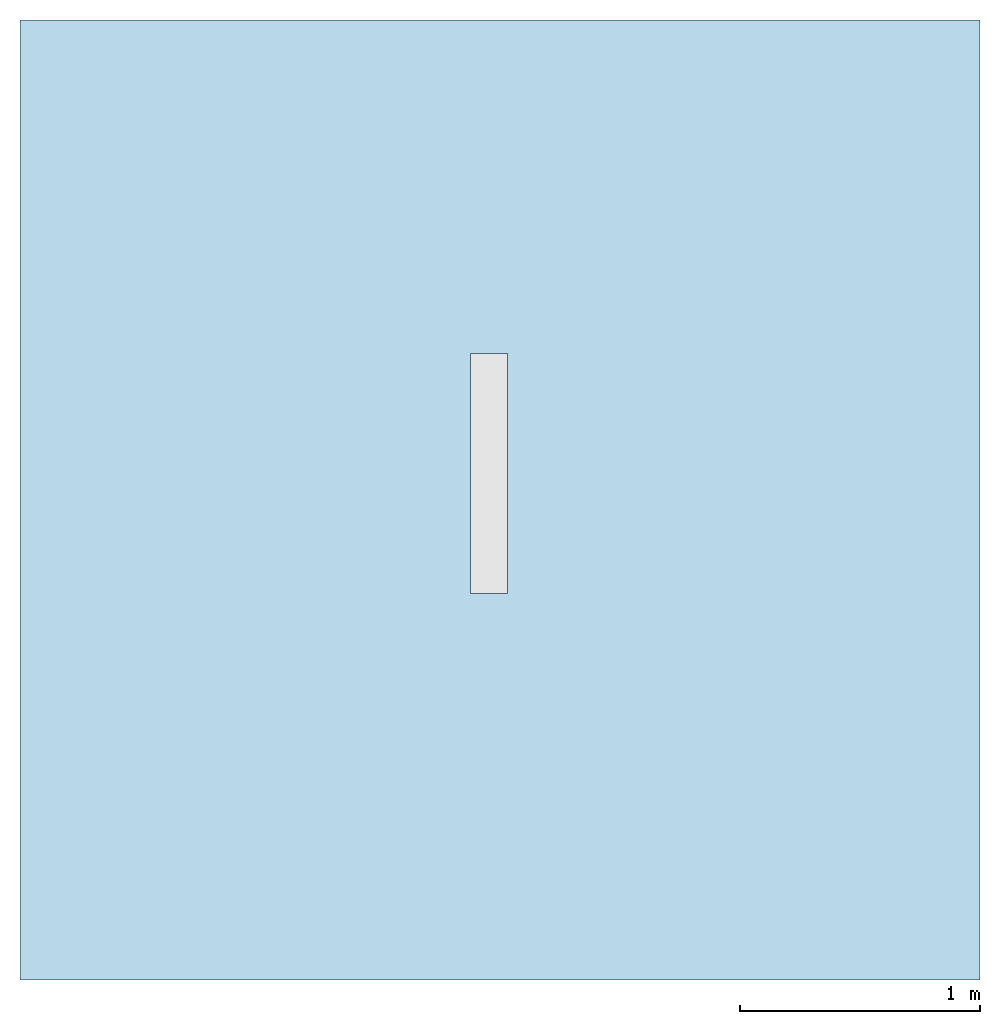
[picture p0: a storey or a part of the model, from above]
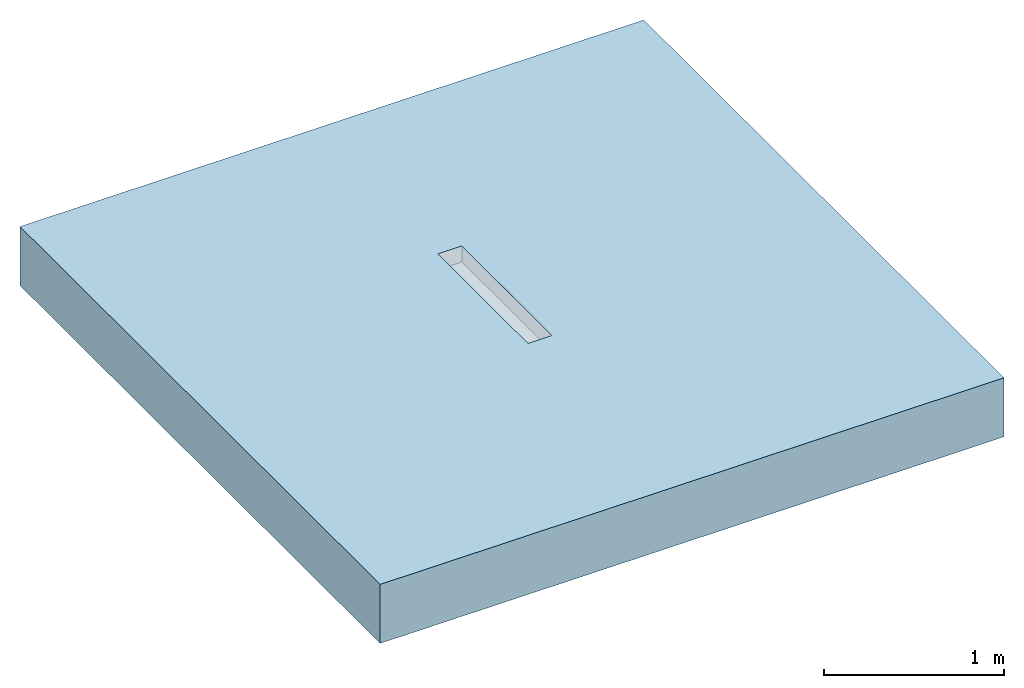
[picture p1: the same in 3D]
Properties of the parts of a building model (IFC2X3)

# File
Description: ViewDefinition [CoordinationView]
File name: 105130 - Straight Channel - 1000mm LG - Invert Depth 95mm.ifc
Time: 2014-03-20T08:44:47
Written by: Autodesk Revit 2013
Made in: 20120221_2030(x64)

# IfcProject, Project Number
LongName: Project Name; Phase: Project Status

# IfcSite, Default
RefLatitude: 42, 21, 30, 344238; RefLongitude: -71, -3, -35, -194702; RefElevation: 0 mm

# IfcBuilding
Pset_BuildingCommon - NumberOfStoreys: 1
Other - Project Address: ## Street City, State Zip; Project Status: Project Status; Client Name: Owner; Project Issue Date: Issue Date; Project Number: Project Number; Project Name: Project Name

# IfcBuildingStorey, Level 1
LongName: Level 1; Elevation: 0 mm
Graphics - Symbol at End 2 Default: yes; Line Pattern: Center; Line Weight: 1; Symbol at End 1 Default: no; Symbol: M_Level Head - Circle: M_Level Head - Circle; Color: 0
Constraints - Elevation Base: 0; Elevation: 0 mm
Dimensions - Computation Height: 0 mm
Identity Data - Structural: no; Name: Level 1; Building Story: yes

# IfcFlowTerminal: 105130 - Straight Channel - 1000mm LG - Invert Depth 95mm, ACO BD Modular 125 Level Invert Straight Channels:105130 - Straight Channel - 1000mm LG - Invert Depth 95mm:105130 - Straight Channel - 1000mm LG - Invert Depth 95mm:202382
In: Level 1
Material: Stainless Steel AISI 304, Polystyrene, High Impact (F)
Dimensions - Grating Length: 1000 mm; Grating End: -1000 mm; Invert Depth Height: 50 mm; Floor Void Height: 107.8 mm; Custom Length: 500 mm; Length: 500 mm; Custom Channel End: -497 mm; Invert Depth: 95 mm; End Connection Plate: 997 mm; Channel End: -997 mm; Height: 95 mm; Standard Length: 1000 mm; Channel Start: -3 mm
Other - PVC Infill (26270): 1000 mm; Rigid PVC Extrusion (49061): 0 mm; Neoprene Gasket: 1; Number: 20; Detail Void Height: 106.3 mm; Flexible PVC Seal (49062): 0 mm; 1000mm Long Channel: yes; Non Standard Length Channel: no; 2000mm Long Channel: no; 500mm Long Channel: no; 3000mm Long Channel: no; Standard Length Channel: yes
Construction - 105530 - Quadrato - Stainless Steel 304 - 500mm long: no; 26270_PVC Infill: yes; 21740 - Ladder - Stainless Steel 304 - 500mm long: no; 105539 - Intercept - Stainless Steel 304 - 500mm long: no; 21741 - Ladder - Stainless Steel 304 - 1000mm long: no; 105844 - Slip Resistant Quadrato Locked - Stainless Steel 304 - 500mm long: no; 10735 - Composite - White Composite - 500mm long: no; 21810 - Grating - Slip Resistant Mesh - Stainless Steel 304 - 1000mm long: no; 105529 - Quadrato - Stainless Steel 304 - 1000mm long: no; 21610 - Grating - Slip Resistant Mesh - Stainless Steel 304 - 1000mm long: no; 21710 - Grating - Slip Resistant Mesh - Stainless Steel 304 - 500mm long: no; End Plate Invert 1: no; 21620 - Grating - Plain Mesh - Stainless Steel 304 - 1000mm long: no; 105842 - Slip Resistant Quadrato - Stainless Steel 304 - 500mm long: no; 96818 - Grating - Heal Safe - Stainless Steel 304 - 1000mm long: no; 105536 - Intercept Locked - Stainless Steel 304 - 1000mm long: no; 105841 - Slip Resistant Quadrato - Stainless Steel 304 - 1000mm long: no; 21720 - Grating - Plain Mesh - Stainless Steel 304 - 500mm long: no; 105847 - Slip Resistant Intercept Locked - Stainless Steel 304 - 1000mm long: no; 105520 - Slotted Locked - Stainless Steel 304 - 1000mm long: no; 105505 - Perforated Locked - Stainless Steel 304 - 500mm long: no; 105846 - Slip Resistant Intercept - Stainless Steel 304 - 500mm long: no; 105843 - Slip Resistant Quadrato Locked - Stainless Steel 304 - 1000mm long: no; 105848 - Slip Resistant Intercept Locked - Stainless Steel 304 - 500mm long: no; 105527 - Quadrato Locked - Stainless Steel 304 - 1000mm long: no; 105519 - Slotted Locked - Stainless Steel 304 - 500mm long: no; 21790 - Plastic - White Plastic - 500mm long: no; 21820 - Grating - Plain Mesh - Stainless Steel 304 - 1000mm long: no; 105537 - Intercept Locked - Stainless Steel 304 - 500mm long: no; 105521 - Slotted Locked - Stainless Steel 304 - 500mm long: no; 105504 - Perforated Locked - Stainless Steel 304 - 1000mm long: no; 402072 - Grating - Heal Safe Locked - Stainless Steel 304 - 500mm long: no; 105845 - Slip Resistant Intercept - Stainless Steel 304 - 1000mm long: no; 105518 - Slotted Locked - Stainless Steel 304 - 1000mm long: no; 49061 & 49062_Vinyl Seal: no; 105528 - Quadrato Locked - Stainless Steel 304 - 500mm long: no; 21910 - Grating - Slip Resistant Mesh - Stainless Steel 304 - 500mm long: no; 105538 - Intercept - Stainless Steel 304 - 1000mm long: no; 402071 - Grating - Heal Safe Locked - Stainless Steel 304 - 1000mm long: no; 15704 - Composite - Black Composite - 500mm long: no; 21690 - Plastic - White Plastic - 1000mm long: no; 96819 - Grating - Heal Safe - Stainless Steel 304 - 500mm long: no; End Plate Invert 2: no; 21920 - Grating - Plain Mesh - Stainless Steel 304 - 500mm long: no; Detail 95mm: yes; Detail 50mm: no; Detail Non Standard Length: no; Detail 125mm: no; Detail 65mm: no; Detail 110mm: no; Detail 80mm: no
Phasing - Phase Created: New Construction
Constraints - Moves With Nearby Elements: no; Level: Level: Level 1
Identity Data - Mark: 1; Manufacturer: ACO Building Drainage; Website: www.acobd.com; E-mail Technical: abdtechnical@aco.co.uk; E-mail Sales: abdcommercial@aco.co.uk; Watermark1: This file is the property of ACO Technologies PLC; Watermarked By: www.acobd.com; Watermarked With: BIM Manager Premium Suite; Address: ACO Business Centre, Caxton Road, Bedford, MK41 0LF; Fax: +44 (0)1462 851490; Telephone: +44 (0)1462 816666; Watermark2: This file is water marked and users are prohibited to reproduce, adapt, distribute this information
General - Product Type: Stainless Steel Channel Drainage System; Product Range: ACO Modular 125; Seal Recyclable: Fully recyclable; Product Standard: BS EN 1433:2002, CE marked; Load Class: A15 - C250; Installation guidelines: X:\Electronic Literature\ABD Electronic Literature\Standard Stainless Steel and Galvanised Steel Channels\ACO Modular 125\ACO Modular 125.pdf; Price: POA - contact ACO; Weight (Kg): 5.0; Channel Recyclable: Fully recyclable; NBS Specification: NBS Section Q10 Kerbs/edgings/channels/paving accessories, Clause 180 Drainage Channel Systems; Channel Recycled Material Content: 60-70%; Seal Colour: Black; Channel Colour: Mid Grey; Maintenance guidelines: X:\Electronic Literature\ABD Electronic Literature\Standard Stainless Steel and Galvanised Steel Channels\ACO Modular 125\ACO Modular 125.pdf; Dimensions (LxWxH): 1000 x 153 x 95; Product Description: ACO Modular 125 Level Invert Channel; Seal Recycled Material Content: 0%; Seal Material: Neoprene; Channel Material: Stainless Steel Grade 304; Product Code: 105130
Model Properties - Grating Product Code 105845: Load Class A15 - Slip Resistant Intercept - Stainless Steel 304 - 1000mm long - 3.6kg; Grating Product Code 21820: Load Class C250 - Plain Mesh - Stainless Steel 304 - 1000mm long - 4.2kg; Grating Product Code 15704: Load Class C250 - Composite - Black Composite - 500mm long - 1.2kg; Grating Product Code 96819: Load Class B125 - Heal Safe - Stainless Steel 304 - 500mm long - 2.0kg; Grating Product Code 21610: Load Class A15 - Slip Resistant Mesh - Stainless Steel 304 - 1000mm long - 3.0kg; Grating Product Code 105521: Load Class C250 - Slotted Locked - Stainless Steel 304 - 500mm long - 2.3kg; Grating Product Code 105520: Load Class C250 - Slotted Locked - Stainless Steel 304 - 1000mm long - 4.7kg; Grating Product Code 105539: Load Class A15 - Intercept - Stainless Steel 304 - 500mm long - 1.8kg; Grating Product Code 21810: Load Class C250 - Slip Resistant Mesh - Stainless Steel 304 - 1000mm long - 4.2kg; Grating Product Code 21710: Load Class A15 - Slip Resistant Mesh - Stainless Steel 304 - 500mm long - 1.6kg; Grating Product Code 105519: Load Class A15 - Slotted Locked - Stainless Steel 304 - 500mm long - 1.0kg; End Plate Product Code 105104: N/A; Grating Product Code 105505: Load Class C250 - Perforated Locked - Stainless Steel 304 - 500mm long - 1.8kg; Grating Product Code 21910: Load Class C250 - Slip Resistant Mesh - Stainless Steel 304 - 500mm long - 2.2kg; End Plate Product Code 105100: N/A; Grating Product Code 105843: Load Class A15 - Slip Resistant Quadrato Locked - Stainless Steel 304 - 1000mm long - 3.2kg; Grating Product Code 105538: Load Class A15 - Intercept - Stainless Steel 304 - 1000mm long - 3.6kg; Grating Product Code 21740: Load Class C250 - Ladder - Stainless Steel 304 - 500mm long - 2.0kg; Grating Product Code 21790: Load Class A15 - Plastic - White Plastic - 500mm long - 0.6kg; Grating Product Code 105527: Load Class A15 - Quadrato Locked - Stainless Steel 304 - 1000mm long - 3.2kg; Grating Product Code 21920: Load Class C250 - Plain Mesh - Stainless Steel 304 - 500mm long - 2.2kg; Grating Product Code 105842: Load Class A15 - Slip Resistant Quadrato - Stainless Steel 304 - 500mm long - 1.6kg; End Plate Product Code 105101: N/A; Grating Product Code 10735: Load Class C250 - Composite - White Composite - 500mm long - 1.2kg; Grating Product Code 105530: Load Class A15 - Quadrato - Stainless Steel 304 - 500mm long - 1.6kg; Grating Product Code 105847: Load Class A15 - Slip Resistant Intercept Locked - Stainless Steel 304 - 1000mm long - 3.6kg; Grating Product Code 402072: Load Class B125 - Heal Safe Locked - Stainless Steel 304 - 500mm long - 2.0kg; Grating Product Code 21620: Load Class A15 - Plain Mesh - Stainless Steel 304 - 1000mm long - 3.0kg; Grating Product Code 105536: Load Class A15 - Intercept Locked - Stainless Steel 304 - 1000mm long - 3.6kg; Grating Product Code 105537: Load Class A15 - Intercept Locked - Stainless Steel 304 - 500mm long - 1.8kg; End Plate Product Code 105105: N/A; Grating Product Code 105528: Load Class A15 - Quadrato Locked - Stainless Steel 304 - 500mm long - 1.6kg; Grating Product Code 105848: Load Class A15 - Slip Resistant Intercept Locked - Stainless Steel 304 - 500mm long - 1.8kg; Grating Product Code 96818: Load Class B125 - Heal Safe - Stainless Steel 304 - 1000mm long - 3.4kg; Grating Product Code 21690: Load Class A15 - Plastic - White Plastic - 1000mm long - 1.2kg; Grating Product Code 105529: Load Class A15 - Quadrato - Stainless Steel 304 - 1000mm long - 3.2kg; Grating Product Code 105846: Load Class A15 - Slip Resistant Intercept - Stainless Steel 304 - 500mm long - 1.8kg; Grating Product Code 21720: Load Class A15 - Plain Mesh - Stainless Steel 304 - 500mm long - 1.6kg; Grating Product Code 105518: Load Class A15 - Slotted Locked - Stainless Steel 304 - 1000mm long - 2.0kg; Grating Product Code 402071: Load Class B125 - Heal Safe Locked - Stainless Steel 304 - 1000mm long - 3.4kg; End Plate Product Code 105103: End Plate Stainless Steel 304 for Invert Depth - 95mm - 0.24Kg; Grating Product Code 105841: Load Class A15 - Slip Resistant Quadrato - Stainless Steel 304 - 1000mm long - 3.2kg; Grating Product Code 105844: Load Class A15 - Slip Resistant Quadrato Locked - Stainless Steel 304 - 500mm long - 1.6kg; Grating Product Code 21741: Load Class C250 - Ladder - Stainless Steel 304 - 1000mm long - 3.4kg; Grating Product Code 105504: Load Class C250 - Perforated Locked - Stainless Steel 304 - 1000mm long - 3.6kg; End Plate Product Code 105102: N/A

# IfcOpeningElement: Recess
In: Level 1
Dimensions - Thickness: 400 mm; Perimeter: 16000 mm; Volume: 6383506609 mm3; Area: 16000000 mm2
Structural - Enable Analytical Model: no; Structural: no
Constraints - Related to Mass: no; Room Bounding: yes; Height Offset From Level: 0 mm; Level: Level: Level 1
Phasing - Phase Created: New Construction
Construction - Default Thickness: 400 mm; Function: 0
Analytical Properties - Roughness: 1; Heat Transfer Coefficient (U): 2.615; Thermal Resistance (R): 0.382409; Thermal mass: 604440; Absorptance: 0.1
Graphics - Coarse Scale Fill Color: 0
Materials and Finishes - Structural Material: Concrete, Broom Finish

# IfcSlab: Floor:Generic Floor - 400mm, Floor:Generic Floor - 400mm:193825
In: Level 1
PredefinedType: FLOOR; Material: Concrete, Broom Finish 400 mm
Dimensions - Thickness: 400 mm; Perimeter: 16000 mm; Volume: 6383506609 mm3; Area: 16000000 mm2
Structural - Enable Analytical Model: no; Structural: no
Constraints - Related to Mass: no; Room Bounding: yes; Height Offset From Level: 0 mm; Level: Level: Level 1
Phasing - Phase Created: New Construction
Pset_SlabCommon - Reference: Generic Floor - 400mm; IsExternal: no; LoadBearing: yes
Construction - Default Thickness: 400 mm; Function: 0
Analytical Properties - Roughness: 1; Heat Transfer Coefficient (U): 2.615; Thermal Resistance (R): 0.382409; Thermal mass: 604440; Absorptance: 0.1
Graphics - Coarse Scale Fill Color: 0
Materials and Finishes - Structural Material: Concrete, Broom Finish
